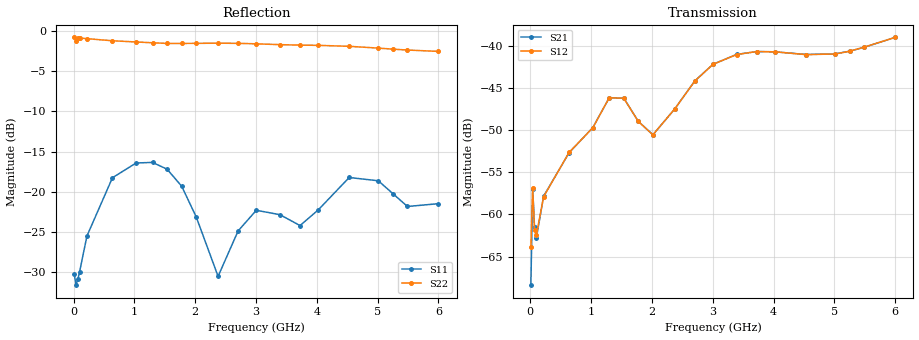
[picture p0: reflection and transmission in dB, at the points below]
!Agilent Technologies,E8364B,MY43040528,A.07.50.67
!Agilent E8364B: A.07.50.67
!Date: Sunday, September 28, 2025 22:02:25
!Correction: S11(Full 2 Port(1,2))
!S21(Full 2 Port(1,2))
!S12(Full 2 Port(1,2))
!S22(Full 2 Port(1,2))
!S2P File: Measurements: S11, S21, S12, S22:
# Hz S  dB  R 50
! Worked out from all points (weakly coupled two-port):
!   201 points, 10 MHz to 6 GHz, reference 50 ohm
!   highest |S21| = -39.01 dB at 6 GHz (marker M1); lowest = -68.4 dB at 10 MHz (marker M2)
!   lowest |S11| = -31.6 dB at 39.95 MHz (marker M3), VSWR 1.05, Z = 52.3 - j1.42 ohm
!   |S11| at or under -10 dB: start of sweep to end of sweep
!   |S22| runs from -2.6 to -0.8 dB; largest |S21 - S12| = 0.00054
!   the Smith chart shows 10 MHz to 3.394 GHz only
!   S11 on the Smith chart (normalised r, x): 10 MHz: 1.04, -0.05; 639 MHz: 0.80, -0.09; 3.394 GHz: 0.97, +0.14
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1e7  -30.17 -44.5  -68.38 99.6  -63.81 43.2  -0.82 -179.9
3.995e7  -31.57 -31.0  -56.95 10.6  -56.86 13.1  -1.32 -176.7
6.99e7  -30.81 -38.5  -61.49 7.2  -61.84 9.1  -0.88 174.5
9.985e7  -29.88 -49.1  -62.82 22.4  -62.46 24.4  -0.90 169.8
2.1965e8  -25.47 -81.7  -57.83 17.8  -57.90 16.9  -0.98 154.9
6.3895e8  -18.24 -151.7  -52.68 -28.4  -52.64 -28.5  -1.24 106.7
1.0283e9  -16.41 158.5  -49.71 -70.8  -49.73 -70.9  -1.39 62.2
1.29785e9  -16.34 126.0  -46.18 -120.6  -46.17 -120.5  -1.49 30.9
1.53745e9  -17.18 95.2  -46.21 172.1  -46.22 172.2  -1.57 2.9
1.77705e9  -19.29 62.0  -48.97 102.5  -48.98 102.5  -1.57 -25.8
2.01665e9  -23.11 23.3  -50.56 27.6  -50.56 27.7  -1.56 -55.1
2.37605e9  -30.48 -90.0  -47.49 -71.0  -47.49 -70.8  -1.54 -99.3
2.7055e9  -24.84 177.5  -44.18 -137.9  -44.19 -137.8  -1.56 -139.2
3.005e9  -22.28 135.5  -42.20 169.4  -42.20 169.5  -1.62 -174.7
3.39435e9  -22.83 99.6  -41.03 107.8  -41.04 107.9  -1.72 140.3
3.7238e9  -24.18 93.0  -40.69 60.5  -40.69 60.7  -1.78 103.0
4.0233e9  -22.23 95.4  -40.72 20.9  -40.72 21.0  -1.81 69.6
4.53245e9  -18.21 62.2  -41.04 -40.9  -41.05 -40.7  -1.93 12.9
5.01165e9  -18.62 21.1  -40.97 -93.4  -40.98 -93.3  -2.15 -42.7
5.25125e9  -20.22 6.6  -40.65 -119.6  -40.65 -119.4  -2.28 -71.8
5.49085e9  -21.81 1.0  -40.18 -146.7  -40.17 -146.5  -2.39 -101.8
6e9  -21.46 -16.5  -39.01 150.4  -39.01 150.6  -2.56 -167.4
